VERSION 5.8 ;
BUSBITCHARS "[]" ;
DIVIDERCHAR "/" ;
UNITS
  DATABASE MICRONS 1000 ;
END UNITS
MANUFACTURINGGRID 0.005 ;

SITE core
  CLASS CORE ;
  SIZE 0.2 BY 1.2 ;
END core

LAYER M1
  TYPE ROUTING ;
  DIRECTION HORIZONTAL ;
  PITCH 0.2 ;
  WIDTH 0.07 ;
  SPACING 0.07 ;
END M1

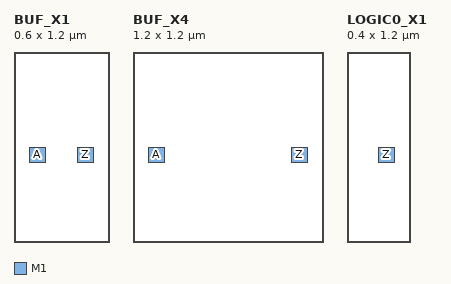
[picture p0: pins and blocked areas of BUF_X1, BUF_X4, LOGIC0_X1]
MACRO BUF_X1
  CLASS CORE ;
  ORIGIN 0 0 ;
  SIZE 0.6 BY 1.2 ;
  SITE core ;
  PIN A
    DIRECTION INPUT ;
    USE SIGNAL ;
    PORT
      LAYER M1 ;
        RECT 0.1 0.5 0.2 0.6 ;
    END
  END A
  PIN Z
    DIRECTION OUTPUT ;
    USE SIGNAL ;
    PORT
      LAYER M1 ;
        RECT 0.4 0.5 0.5 0.6 ;
    END
  END Z
END BUF_X1

MACRO BUF_X4
  CLASS CORE ;
  ORIGIN 0 0 ;
  SIZE 1.2 BY 1.2 ;
  SITE core ;
  PIN A
    DIRECTION INPUT ;
    USE SIGNAL ;
    PORT
      LAYER M1 ;
        RECT 0.1 0.5 0.2 0.6 ;
    END
  END A
  PIN Z
    DIRECTION OUTPUT ;
    USE SIGNAL ;
    PORT
      LAYER M1 ;
        RECT 1.0 0.5 1.1 0.6 ;
    END
  END Z
END BUF_X4

MACRO LOGIC0_X1
  CLASS CORE ;
  ORIGIN 0 0 ;
  SIZE 0.4 BY 1.2 ;
  SITE core ;
  PIN Z
    DIRECTION OUTPUT ;
    USE SIGNAL ;
    PORT
      LAYER M1 ;
        RECT 0.2 0.5 0.3 0.6 ;
    END
  END Z
END LOGIC0_X1

END LIBRARY
